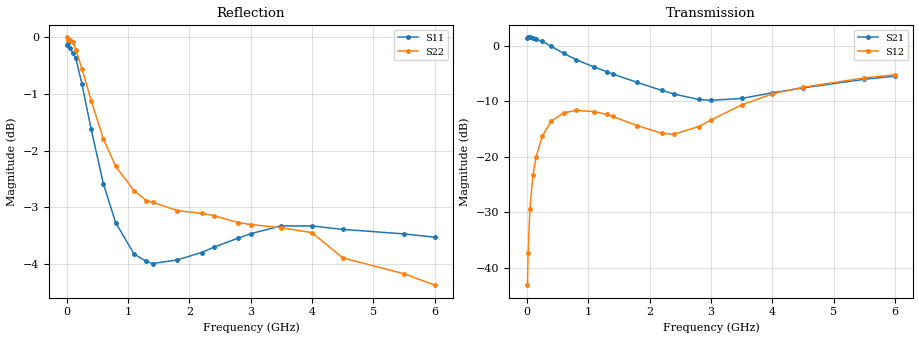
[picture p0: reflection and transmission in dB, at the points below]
! Infineon Technologies  Discrete & RF Semiconductors
! BFS17W
! Si NPN RF Bipolar Junction Transistor in SOT323
! VCE = 0.75 V  IC = 0.3 mA
! Common Emitter S-Parameters:  August  1999
# GHz  S  MA  R  50
!  f  S11  S21  S12  S22
! GHz  MAG  ANG  MAG  ANG  MAG  ANG  MAG  ANG
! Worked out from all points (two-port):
!   36 points, 10 MHz to 6 GHz, reference 50 ohm
!   highest |S21| = 1.55 dB at 20 MHz (marker M1); lowest = -9.8 dB at 3 GHz (marker M2)
!   |S21| within 3 dB of the highest: start of sweep to 618.9 MHz
!   lowest |S11| = -4.0 dB at 1.4 GHz (marker M3), VSWR 4.43, Z = 11.6 - j7.67 ohm
!   |S11| at or under -10 dB: nowhere
!   |S22| runs from -4.4 to 0.0 dB; largest |S21 - S12| = 1.2
!   S11 on the Smith chart (normalised r, x): 10 MHz: 24, -48; 250 MHz: 0.29, -2.23; 600 MHz: 0.25, -0.83; 1.3 GHz: 0.23, -0.20; 2.8 GHz: 0.22, +0.34; 6 GHz: 0.46, +1.09
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0.01  0.9837 -1.9  1.192 179.0  0.007 90.2  0.9999 -0.3
0.02  0.9891 -4.2  1.196 176.5  0.0137 87.7  0.9951 -1.4
0.05  0.9792 -10.0  1.196 170.8  0.0343 83.4  0.9954 -3.8
0.1  0.9685 -19.6  1.175 162.1  0.0687 77.1  0.9909 -7.5
0.15  0.9587 -30.0  1.158 152.8  0.0996 70.4  0.9742 -11.1
0.25  0.9094 -47.8  1.099 136.1  0.1536 58.7  0.9385 -17.5
0.4  0.8295 -72.2  0.994 113.9  0.2107 44.5  0.8793 -25.5
0.6  0.7422 -98.5  0.857 90.7  0.2498 30.3  0.8133 -33.6
0.8  0.6861 -119.0  0.755 72.9  0.2631 20.1  0.7693 -40.8
1.1  0.6437 -143.1  0.645 52.8  0.2563 10.0  0.7322 -51.0
1.3  0.6342 -156.3  0.588 42.9  0.2421 5.5  0.7178 -58.2
1.4  0.6315 -161.6  0.559 38.5  0.2318 4.1  0.7154 -61.6
1.8  0.6361 178.4  0.47 25.5  0.1915 4.6  0.7033 -76.6
2.2  0.6458 162.4  0.398 19.0  0.1631 16.2  0.6992 -91.5
2.4  0.6528 155.0  0.369 18.1  0.1604 25.3  0.6961 -99.2
2.8  0.6651 141.2  0.33 20.2  0.1881 41.4  0.6862 -114.1
3  0.671 135.0  0.324 22.7  0.2151 45.9  0.6836 -120.9
3.5  0.6817 120.9  0.337 28.7  0.2943 48.3  0.6792 -138.5
4  0.6816 109.2  0.379 30.8  0.37 43.8  0.6724 -155.9
4.5  0.6769 99.2  0.419 29.6  0.4249 37.9  0.6388 -171.0
5.5  0.6707 84.8  0.502 22.5  0.5162 26.5  0.6185 164.5
6  0.6662 79.4  0.534 18.1  0.5511 21.1  0.6044 153.8
